VERSION 5.7 ;
  NOWIREEXTENSIONATPIN ON ;
  DIVIDERCHAR "/" ;
  BUSBITCHARS "[]" ;
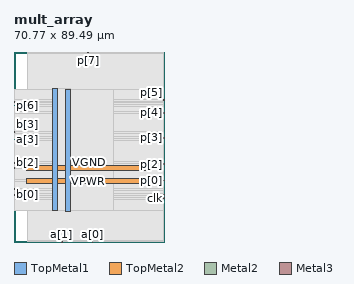
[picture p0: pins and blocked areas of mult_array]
MACRO mult_array
  CLASS BLOCK ;
  FOREIGN mult_array ;
  ORIGIN 0.000 0.000 ;
  SIZE 70.770 BY 89.490 ;
  PIN VGND
    DIRECTION INOUT ;
    USE GROUND ;
    PORT
      LAYER TopMetal1 ;
        RECT 24.460 14.490 26.660 72.040 ;
    END
    PORT
      LAYER TopMetal2 ;
        RECT 5.760 33.820 64.800 36.020 ;
    END
  END VGND
  PIN VPWR
    DIRECTION INOUT ;
    USE POWER ;
    PORT
      LAYER TopMetal1 ;
        RECT 18.260 14.900 20.460 72.450 ;
    END
    PORT
      LAYER TopMetal2 ;
        RECT 5.760 27.620 64.800 29.820 ;
    END
  END VPWR
  PIN a[0]
    DIRECTION INPUT ;
    USE SIGNAL ;
    ANTENNAGATEAREA 0.180700 ;
    PORT
      LAYER Metal2 ;
        RECT 36.760 0.000 37.160 0.400 ;
    END
  END a[0]
  PIN a[1]
    DIRECTION INPUT ;
    USE SIGNAL ;
    ANTENNAGATEAREA 0.180700 ;
    PORT
      LAYER Metal2 ;
        RECT 22.360 0.000 22.760 0.400 ;
    END
  END a[1]
  PIN a[2]
    DIRECTION INPUT ;
    USE SIGNAL ;
    ANTENNAGATEAREA 0.180700 ;
    PORT
      LAYER Metal3 ;
        RECT 0.000 34.660 0.400 35.060 ;
    END
  END a[2]
  PIN a[3]
    DIRECTION INPUT ;
    USE SIGNAL ;
    ANTENNAGATEAREA 0.180700 ;
    PORT
      LAYER Metal3 ;
        RECT 0.000 48.100 0.400 48.500 ;
    END
  END a[3]
  PIN b[0]
    DIRECTION INPUT ;
    USE SIGNAL ;
    ANTENNAGATEAREA 0.180700 ;
    PORT
      LAYER Metal3 ;
        RECT 0.000 22.060 0.400 22.460 ;
    END
  END b[0]
  PIN b[1]
    DIRECTION INPUT ;
    USE SIGNAL ;
    ANTENNAGATEAREA 0.180700 ;
    PORT
      LAYER Metal3 ;
        RECT 0.000 24.580 0.400 24.980 ;
    END
  END b[1]
  PIN b[2]
    DIRECTION INPUT ;
    USE SIGNAL ;
    ANTENNAGATEAREA 0.180700 ;
    PORT
      LAYER Metal3 ;
        RECT 0.000 37.180 0.400 37.580 ;
    END
  END b[2]
  PIN b[3]
    DIRECTION INPUT ;
    USE SIGNAL ;
    ANTENNAGATEAREA 0.180700 ;
    PORT
      LAYER Metal3 ;
        RECT 0.000 51.460 0.400 51.860 ;
    END
  END b[3]
  PIN clk
    DIRECTION INPUT ;
    USE SIGNAL ;
    ANTENNAGATEAREA 1.450800 ;
    PORT
      LAYER Metal3 ;
        RECT 70.370 20.380 70.770 20.780 ;
    END
  END clk
  PIN p[0]
    DIRECTION OUTPUT ;
    USE SIGNAL ;
    ANTENNADIFFAREA 0.708600 ;
    PORT
      LAYER Metal3 ;
        RECT 70.370 28.780 70.770 29.180 ;
    END
  END p[0]
  PIN p[1]
    DIRECTION OUTPUT ;
    USE SIGNAL ;
    ANTENNADIFFAREA 0.708600 ;
    PORT
      LAYER Metal3 ;
        RECT 70.370 22.060 70.770 22.460 ;
    END
  END p[1]
  PIN p[2]
    DIRECTION OUTPUT ;
    USE SIGNAL ;
    ANTENNADIFFAREA 0.708600 ;
    PORT
      LAYER Metal3 ;
        RECT 70.370 36.340 70.770 36.740 ;
    END
  END p[2]
  PIN p[3]
    DIRECTION OUTPUT ;
    USE SIGNAL ;
    ANTENNADIFFAREA 0.708600 ;
    PORT
      LAYER Metal3 ;
        RECT 70.370 48.940 70.770 49.340 ;
    END
  END p[3]
  PIN p[4]
    DIRECTION OUTPUT ;
    USE SIGNAL ;
    ANTENNADIFFAREA 0.708600 ;
    PORT
      LAYER Metal3 ;
        RECT 70.370 60.700 70.770 61.100 ;
    END
  END p[4]
  PIN p[5]
    DIRECTION OUTPUT ;
    USE SIGNAL ;
    ANTENNADIFFAREA 0.708600 ;
    PORT
      LAYER Metal3 ;
        RECT 70.370 66.580 70.770 66.980 ;
    END
  END p[5]
  PIN p[6]
    DIRECTION OUTPUT ;
    USE SIGNAL ;
    ANTENNADIFFAREA 0.708600 ;
    PORT
      LAYER Metal3 ;
        RECT 0.000 64.060 0.400 64.460 ;
    END
  END p[6]
  PIN p[7]
    DIRECTION OUTPUT ;
    USE SIGNAL ;
    ANTENNADIFFAREA 0.708600 ;
    PORT
      LAYER Metal2 ;
        RECT 34.840 89.090 35.240 89.490 ;
    END
  END p[7]
  PIN rst_n
    DIRECTION INPUT ;
    USE SIGNAL ;
    ANTENNAGATEAREA 0.180700 ;
    PORT
      LAYER Metal3 ;
        RECT 0.000 65.740 0.400 66.140 ;
    END
  END rst_n
  OBS
      LAYER GatPoly ;
        RECT 5.760 14.970 64.800 71.970 ;
      LAYER Metal1 ;
        RECT 5.760 14.900 64.800 72.040 ;
      LAYER Metal2 ;
        RECT 6.135 88.880 34.630 89.090 ;
        RECT 35.450 88.880 70.185 89.090 ;
        RECT 6.135 0.610 70.185 88.880 ;
        RECT 6.135 0.100 22.150 0.610 ;
        RECT 22.970 0.100 36.550 0.610 ;
        RECT 37.370 0.100 70.185 0.610 ;
      LAYER Metal3 ;
        RECT 0.400 67.190 70.370 71.920 ;
        RECT 0.400 66.370 70.160 67.190 ;
        RECT 0.400 66.350 70.370 66.370 ;
        RECT 0.610 65.530 70.370 66.350 ;
        RECT 0.400 64.670 70.370 65.530 ;
        RECT 0.610 63.850 70.370 64.670 ;
        RECT 0.400 61.310 70.370 63.850 ;
        RECT 0.400 60.490 70.160 61.310 ;
        RECT 0.400 52.070 70.370 60.490 ;
        RECT 0.610 51.250 70.370 52.070 ;
        RECT 0.400 49.550 70.370 51.250 ;
        RECT 0.400 48.730 70.160 49.550 ;
        RECT 0.400 48.710 70.370 48.730 ;
        RECT 0.610 47.890 70.370 48.710 ;
        RECT 0.400 37.790 70.370 47.890 ;
        RECT 0.610 36.970 70.370 37.790 ;
        RECT 0.400 36.950 70.370 36.970 ;
        RECT 0.400 36.130 70.160 36.950 ;
        RECT 0.400 35.270 70.370 36.130 ;
        RECT 0.610 34.450 70.370 35.270 ;
        RECT 0.400 29.390 70.370 34.450 ;
        RECT 0.400 28.570 70.160 29.390 ;
        RECT 0.400 25.190 70.370 28.570 ;
        RECT 0.610 24.370 70.370 25.190 ;
        RECT 0.400 22.670 70.370 24.370 ;
        RECT 0.610 21.850 70.160 22.670 ;
        RECT 0.400 20.990 70.370 21.850 ;
        RECT 0.400 20.170 70.160 20.990 ;
        RECT 0.400 15.020 70.370 20.170 ;
      LAYER Metal4 ;
        RECT 18.440 14.975 46.660 71.965 ;
      LAYER Metal5 ;
        RECT 18.395 14.810 26.525 72.130 ;
  END
END mult_array
END LIBRARY

